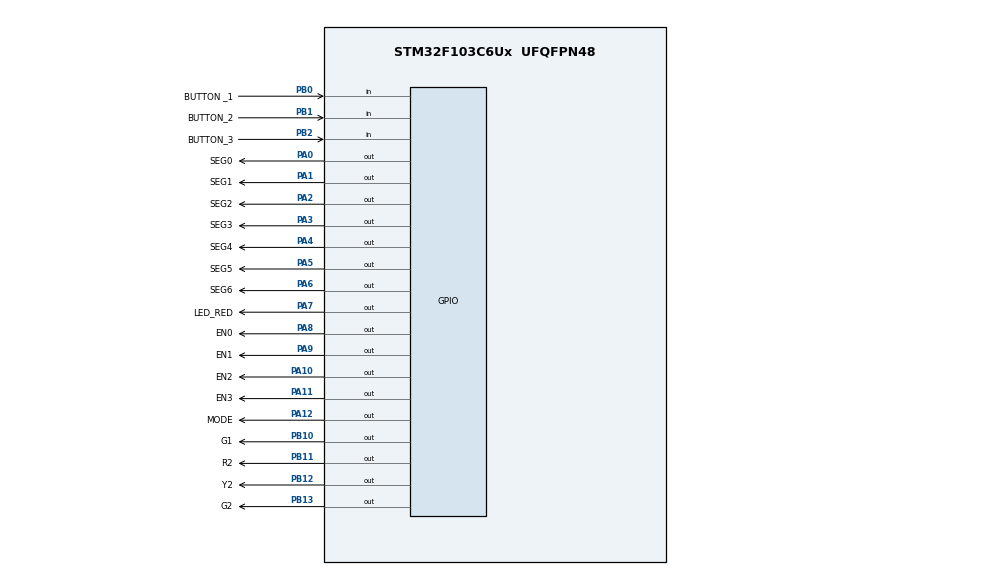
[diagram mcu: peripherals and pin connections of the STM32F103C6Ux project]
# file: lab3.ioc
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Mcu.Family=STM32F1
Mcu.Name=STM32F103C6Ux
Mcu.Package=UFQFPN48
NVIC.PriorityGroup=NVIC_PRIORITYGROUP_4
NVIC.TIM2_IRQn=true\:0\:0\:false\:false\:true\:true\:true
PA0-WKUP.GPIO_Label=SEG0
PA0-WKUP.Signal=GPIO_Output
PA1.GPIO_Label=SEG1
PA1.Signal=GPIO_Output
PA10.GPIO_Label=EN2
PA10.Signal=GPIO_Output
PA11.GPIO_Label=EN3
PA11.Signal=GPIO_Output
PA12.GPIO_Label=MODE
PA12.Signal=GPIO_Output
PA2.GPIO_Label=SEG2
PA2.Signal=GPIO_Output
PA3.GPIO_Label=SEG3
PA3.Signal=GPIO_Output
PA4.GPIO_Label=SEG4
PA4.Signal=GPIO_Output
PA5.GPIO_Label=SEG5
PA5.Signal=GPIO_Output
PA6.GPIO_Label=SEG6
PA6.Signal=GPIO_Output
PA7.GPIO_Label=LED_RED
PA7.Signal=GPIO_Output
PA8.GPIO_Label=EN0
PA8.Signal=GPIO_Output
PA9.GPIO_Label=EN1
PA9.Signal=GPIO_Output
PB0.GPIO_Label=BUTTON _1
PB0.Signal=GPIO_Input
PB1.GPIO_Label=BUTTON_2
PB1.Signal=GPIO_Input
PB10.GPIO_Label=G1
PB10.Signal=GPIO_Output
PB11.GPIO_Label=R2
PB11.Signal=GPIO_Output
PB12.GPIO_Label=Y2
PB12.Signal=GPIO_Output
PB13.GPIO_Label=G2
PB13.Signal=GPIO_Output
PB2.GPIO_Label=BUTTON_3
PB2.Signal=GPIO_Input
ProjectManager.HeapSize=0x200
ProjectManager.StackSize=0x400
ProjectManager.TargetToolchain=STM32CubeIDE
RCC.APB1Freq_Value=8000000
RCC.APB2Freq_Value=8000000
TIM2.Period=9
TIM2.Prescaler=7999
VP_SYS_VS_ND.Mode=No_Debug
VP_TIM2_VS_ClockSourceINT.Mode=Internal
board=custom

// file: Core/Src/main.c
/* USER CODE BEGIN Header */
/**
  ******************************************************************************
  * @file           : main.c
  * @brief          : Main program body
  ******************************************************************************
  * @attention
  *
  * Copyright (c) 2023 STMicroelectronics.
  * All rights reserved.
  *
  * This software is licensed under terms that can be found in the LICENSE file
  * in the root directory of this software component.
  * If no LICENSE file comes with this software, it is provided AS-IS.
  *
  ******************************************************************************
  */
/* USER CODE END Header */
#include "main.h"

/* USER CODE BEGIN Includes */
#include "input_processing.h"
#include "led_display.h"
#include "input_reading.h"
#include "timer.h"
/* USER CODE END Includes */

 TIM_HandleTypeDef htim2;

void SystemClock_Config(void);
static void MX_GPIO_Init(void);
static void MX_TIM2_Init(void);

int main(void)
{

  /* MCU Configuration--------------------------------------------------------*/

  /* Reset of all peripherals, Initializes the Flash interface and the Systick. */
  HAL_Init();

  /* Configure the system clock */
  SystemClock_Config();

  /* Initialize all configured peripherals */
  MX_GPIO_Init();
  MX_TIM2_Init();
  /* USER CODE BEGIN 2 */
  HAL_TIM_Base_Start_IT(&htim2);
  /* USER CODE END 2 */

  /* Infinite loop */
  /* USER CODE BEGIN WHILE */
  init_buffer();
  LedTimeDurationInit();
  setTimer0(1);
  setTimer1(1);
  setTimer2(1);
  setTimer3(1);
  while (1)
  {
	  UpdateMode();
	  if (get_timer2_flag()) {
		  LEDScanning();
		  setTimer2(1);
	  }

	  LedDispMode();
	  UpdateDurationValue();

	  if (get_timer1_flag()) {
		  HAL_GPIO_TogglePin(LED_RED_GPIO_Port, LED_RED_Pin);
		  setTimer1(500);
	  }

    /* USER CODE END WHILE */

  }
}

void SystemClock_Config(void)
{
  RCC_OscInitTypeDef RCC_OscInitStruct = {0};
  RCC_ClkInitTypeDef RCC_ClkInitStruct = {0};

  /** Initializes the RCC Oscillators according to the specified parameters
  * in the RCC_OscInitTypeDef structure.
  */
  RCC_OscInitStruct.OscillatorType = RCC_OSCILLATORTYPE_HSI;
  RCC_OscInitStruct.HSIState = RCC_HSI_ON;
  RCC_OscInitStruct.HSICalibrationValue = RCC_HSICALIBRATION_DEFAULT;
  RCC_OscInitStruct.PLL.PLLState = RCC_PLL_NONE;
  if (HAL_RCC_OscConfig(&RCC_OscInitStruct) != HAL_OK)
  {
    Error_Handler();
  }

  /** Initializes the CPU, AHB and APB buses clocks
  */
  RCC_ClkInitStruct.ClockType = RCC_CLOCKTYPE_HCLK|RCC_CLOCKTYPE_SYSCLK
                              |RCC_CLOCKTYPE_PCLK1|RCC_CLOCKTYPE_PCLK2;
  RCC_ClkInitStruct.SYSCLKSource = RCC_SYSCLKSOURCE_HSI;
  RCC_ClkInitStruct.AHBCLKDivider = RCC_SYSCLK_DIV1;
  RCC_ClkInitStruct.APB1CLKDivider = RCC_HCLK_DIV1;
  RCC_ClkInitStruct.APB2CLKDivider = RCC_HCLK_DIV1;

  if (HAL_RCC_ClockConfig(&RCC_ClkInitStruct, FLASH_LATENCY_0) != HAL_OK)
  {
    Error_Handler();
  }
}

static void MX_TIM2_Init(void)
{

  TIM_ClockConfigTypeDef sClockSourceConfig = {0};
  TIM_MasterConfigTypeDef sMasterConfig = {0};

  htim2.Instance = TIM2;
  htim2.Init.Prescaler = 7999;
  htim2.Init.CounterMode = TIM_COUNTERMODE_UP;
  htim2.Init.Period = 9;
  htim2.Init.ClockDivision = TIM_CLOCKDIVISION_DIV1;
  htim2.Init.AutoReloadPreload = TIM_AUTORELOAD_PRELOAD_DISABLE;
  if (HAL_TIM_Base_Init(&htim2) != HAL_OK)
  {
    Error_Handler();
  }
  sClockSourceConfig.ClockSource = TIM_CLOCKSOURCE_INTERNAL;
  if (HAL_TIM_ConfigClockSource(&htim2, &sClockSourceConfig) != HAL_OK)
  {
    Error_Handler();
  }
  sMasterConfig.MasterOutputTrigger = TIM_TRGO_RESET;
  sMasterConfig.MasterSlaveMode = TIM_MASTERSLAVEMODE_DISABLE;
  if (HAL_TIMEx_MasterConfigSynchronization(&htim2, &sMasterConfig) != HAL_OK)
  {
    Error_Handler();
  }

}

static void MX_GPIO_Init(void)
{
  GPIO_InitTypeDef GPIO_InitStruct = {0};

  /* GPIO Ports Clock Enable */
  __HAL_RCC_GPIOA_CLK_ENABLE();
  __HAL_RCC_GPIOB_CLK_ENABLE();

  /*Configure GPIO pin Output Level */
  HAL_GPIO_WritePin(GPIOA, SEG0_Pin|SEG1_Pin|SEG2_Pin|SEG3_Pin
                          |SEG4_Pin|SEG5_Pin|SEG6_Pin|LED_RED_Pin
                          |EN0_Pin|EN1_Pin|EN2_Pin|EN3_Pin
                          |MODE_Pin, GPIO_PIN_RESET);

  /*Configure GPIO pin Output Level */
  HAL_GPIO_WritePin(GPIOB, G1_Pin|R2_Pin|Y2_Pin|G2_Pin
                          |R1_Pin|Y1_Pin, GPIO_PIN_RESET);

  /*Configure GPIO pins : SEG0_Pin SEG1_Pin SEG2_Pin SEG3_Pin
                           SEG4_Pin SEG5_Pin SEG6_Pin LED_RED_Pin
                           EN0_Pin EN1_Pin EN2_Pin EN3_Pin
                           MODE_Pin */
  GPIO_InitStruct.Pin = SEG0_Pin|SEG1_Pin|SEG2_Pin|SEG3_Pin
                          |SEG4_Pin|SEG5_Pin|SEG6_Pin|LED_RED_Pin
                          |EN0_Pin|EN1_Pin|EN2_Pin|EN3_Pin
                          |MODE_Pin;
  GPIO_InitStruct.Mode = GPIO_MODE_OUTPUT_PP;
  GPIO_InitStruct.Pull = GPIO_NOPULL;
  GPIO_InitStruct.Speed = GPIO_SPEED_FREQ_LOW;
  HAL_GPIO_Init(GPIOA, &GPIO_InitStruct);

  /*Configure GPIO pins : BUTTON_1_Pin BUTTON_2_Pin BUTTON_3_Pin */
  GPIO_InitStruct.Pin = BUTTON_1_Pin|BUTTON_2_Pin|BUTTON_3_Pin;
  GPIO_InitStruct.Mode = GPIO_MODE_INPUT;
  GPIO_InitStruct.Pull = GPIO_NOPULL;
  HAL_GPIO_Init(GPIOB, &GPIO_InitStruct);

  /*Configure GPIO pins : G1_Pin R2_Pin Y2_Pin G2_Pin
                           R1_Pin Y1_Pin */
  GPIO_InitStruct.Pin = G1_Pin|R2_Pin|Y2_Pin|G2_Pin
                          |R1_Pin|Y1_Pin;
  GPIO_InitStruct.Mode = GPIO_MODE_OUTPUT_PP;
  GPIO_InitStruct.Pull = GPIO_NOPULL;
  GPIO_InitStruct.Speed = GPIO_SPEED_FREQ_LOW;
  HAL_GPIO_Init(GPIOB, &GPIO_InitStruct);

}

void Error_Handler(void)
{
  __disable_irq();
  while (1)
  {
  }
}
